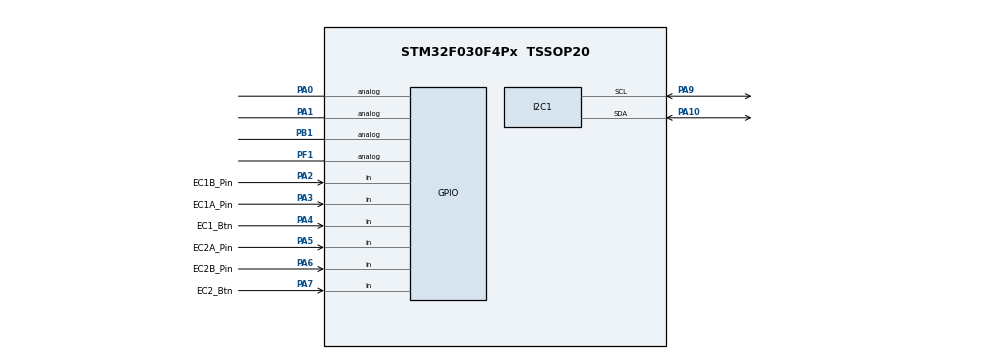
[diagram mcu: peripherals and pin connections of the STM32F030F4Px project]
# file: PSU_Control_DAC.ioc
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Mcu.Family=STM32F0
Mcu.Name=STM32F030F4Px
Mcu.Package=TSSOP20
Mcu.UserConstants=SCAN_PERIOD_US,100
NVIC.TIM14_IRQn=true\:0\:0\:false\:false\:true\:true\:true
PA0.Signal=GPIO_Analog
PA1.Signal=GPIO_Analog
PA10.Mode=I2C
PA10.Signal=I2C1_SDA
PA13.Mode=Serial_Wire
PA13.Signal=SYS_SWDIO
PA14.Mode=Serial_Wire
PA14.Signal=SYS_SWCLK
PA2.GPIO_Label=EC1B_Pin
PA2.Signal=GPIO_Input
PA3.GPIO_Label=EC1A_Pin
PA3.Signal=GPIO_Input
PA4.GPIO_Label=EC1_Btn
PA4.Signal=GPIO_Input
PA5.GPIO_Label=EC2A_Pin
PA5.Signal=GPIO_Input
PA6.GPIO_Label=EC2B_Pin
PA6.Signal=GPIO_Input
PA7.GPIO_Label=EC2_Btn
PA7.Signal=GPIO_Input
PA9.Mode=I2C
PA9.Signal=I2C1_SCL
PB1.Signal=GPIO_Analog
PF0-OSC_IN.Mode=HSE-External-Clock-Source
PF0-OSC_IN.Signal=RCC_OSC_IN
PF1-OSC_OUT.Signal=GPIO_Analog
ProjectManager.HeapSize=0x200
ProjectManager.StackSize=0x400
ProjectManager.TargetToolchain=STM32CubeIDE
RCC.PLLSourceVirtual=RCC_PLLSOURCE_HSE
RCC.SYSCLKSource=RCC_SYSCLKSOURCE_HSE
TIM14.Period=SCAN_PERIOD_US-1
TIM14.Prescaler=7
VP_TIM14_VS_ClockSourceINT.Mode=Enable_Timer
board=custom

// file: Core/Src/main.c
/* USER CODE BEGIN Header */
/**
  ******************************************************************************
  * @file           : main.c
  * @brief          : Main program body
  ******************************************************************************
  * @attention
  *
  * <h2><center>&copy; Copyright (c) 2024 STMicroelectronics.
  * All rights reserved.</center></h2>
  *
  * This software component is licensed by ST under BSD 3-Clause license,
  * the "License"; You may not use this file except in compliance with the
  * License. You may obtain a copy of the License at:
  *                        opensource.org/licenses/BSD-3-Clause
  *
  ******************************************************************************
  */
/* USER CODE END Header */
#include "main.h"

/* USER CODE BEGIN Includes */
#include "board_controls.h"
#include "mcp4725.h"
#include "calibration.h"
/* USER CODE END Includes */

/* USER CODE BEGIN PD */
#define CURRENT_DAC_ADDR		0x60
#define VOLTAGE_DAC_ADDR		0x61

#define SAVE_EEPROM_DELAY_MS	2000
#define SAVE_EEPROM_DELAY_CNTR	(SAVE_EEPROM_DELAY_MS/STATE_SCAN_PERIOD_MS)

#define STEP_50MV				1
#define STEP_250MV				5
#define STEP_10MA				1
#define STEP_100MA				10
/* USER CODE END PD */

I2C_HandleTypeDef hi2c1;

TIM_HandleTypeDef htim14;

/* USER CODE BEGIN PV */
volatile uint8_t is_scan_event = 0;
uint16_t voltageDacVal = 0, currentDacVal = 0;
uint16_t voltageDacValIdx = 0, currentDacValIdx = 0;

uint16_t voltageValStepArray[2] = {STEP_50MV, STEP_250MV}, currentValStepArray[2] = {STEP_10MA, STEP_100MA};
uint8_t voltageValStepIdx = 0, currentValStepIdx = 0;
uint16_t voltageValStep = STEP_50MV, currentValStep = STEP_10MA;
/* USER CODE END PV */

void SystemClock_Config(void);
static void MX_GPIO_Init(void);
static void MX_I2C1_Init(void);
static void MX_TIM14_Init(void);
/* USER CODE BEGIN PFP */
static void checkDacValLimits(uint16_t* val, uint16_t min, uint16_t max);
static void checkIndexValLimits(uint16_t* val, uint16_t min, uint16_t max);
static uint8_t checkSaveDacValueInEEPROM(uint16_t* delay_cntr);
static uint16_t getDacSavedValueIdx(uint16_t* values, uint16_t max_index, uint16_t saved_val);
/* USER CODE END PFP */

int main(void)
{
  /* USER CODE BEGIN 1 */
  EncoderState enc1 = {0, NotPressed, 0}, enc2 = {0, NotPressed, 0};
  uint16_t saveVoltageValDelayCntr = SAVE_EEPROM_DELAY_CNTR+1, saveCurrentValDelayCntr = SAVE_EEPROM_DELAY_CNTR+1; // no need to save already saved DAC value
  /* USER CODE END 1 */

  /* MCU Configuration--------------------------------------------------------*/

  /* Reset of all peripherals, Initializes the Flash interface and the Systick. */
  HAL_Init();

  /* Configure the system clock */
  SystemClock_Config();

  /* Initialize all configured peripherals */
  MX_GPIO_Init();
  MX_I2C1_Init();
  MX_TIM14_Init();
  /* USER CODE BEGIN 2 */
  // check DACs present on I2C bus and read last saved value from EEPROM
  if(MCP4725_check(VOLTAGE_DAC_ADDR))
  {
	  voltageDacVal = MCP4725_readDAC_register_and_EEPROM(VOLTAGE_DAC_ADDR, DAC_EEPROM_VALUE);
  }
  voltageDacValIdx = getDacSavedValueIdx((uint16_t*)voltage_set_50mv_step, VOLTAGE_MAX_INDEX, voltageDacVal);

  HAL_Delay(100);

  if(MCP4725_check(CURRENT_DAC_ADDR))
  {
	  currentDacVal = MCP4725_readDAC_register_and_EEPROM(CURRENT_DAC_ADDR, DAC_EEPROM_VALUE);
  }
  currentDacValIdx = getDacSavedValueIdx((uint16_t*)current_set_10ma_step, CURRENT_MAX_INDEX, currentDacVal);
  // start encoder scanning timer
  HAL_TIM_Base_Start_IT(&htim14);
  /* USER CODE END 2 */

  /* Infinite loop */
  while (1)
  {

    /* USER CODE BEGIN 3 */
	  if(is_scan_event)
	  {
		  is_scan_event = 0; // reset flag

		  // get encoders state
		  if(scanEncoders(&enc1, &enc2))
		  {
			  // check is encoder 1 state changed
			  if(enc1.is_state_changed)
			  {
				  // set DAC value, if encoder counter value is changed
				  if(enc1.counter_offset != 0)
				  {
					  saveVoltageValDelayCntr = 0; // reset counter
					  voltageDacValIdx += (enc1.counter_offset*voltageValStep);
					  checkIndexValLimits(&voltageDacValIdx, 0, VOLTAGE_MAX_INDEX);
					  voltageDacVal = voltage_set_50mv_step[voltageDacValIdx];
//					  checkDacValLimits(&voltageDacVal, VOLTAGE_MIN_VAL, VOLTAGE_MAX_VAL);
					  MCP4725_writeDAC_register(VOLTAGE_DAC_ADDR, voltageDacVal, 0);
				  }
				  else
				  {
					  // save current DAC value in EEPROM, if it wasn't changed by 2 sec
					  if(checkSaveDacValueInEEPROM(&saveVoltageValDelayCntr))
					  {
						  MCP4725_writeDAC_register(VOLTAGE_DAC_ADDR, voltageDacVal, 1);
					  }
				  }

				  // set DAC value change step, if encoder button is pressed
				  if(enc1.btn_state == Pressed)
				  {
					  voltageValStepIdx ^= 0x01;
					  voltageValStep = voltageValStepArray[voltageValStepIdx];
				  }
				  else if(enc1.btn_state == LongPressed)
				  {
					  voltageValStep = 1; // set maximum accuracy
				  }
			  }
			  else
			  {
				  // save current DAC value in EEPROM, if it wasn't changed by 2 sec
				  if(checkSaveDacValueInEEPROM(&saveVoltageValDelayCntr))
				  {
					  MCP4725_writeDAC_register(VOLTAGE_DAC_ADDR, voltageDacVal, 1);
				  }
			  }

			  // check is encoder 2 state changed
			  if(enc2.is_state_changed)
			  {
				  // set DAC value, if encoder counter value is changed
				  if(enc2.counter_offset != 0)
				  {
					  saveCurrentValDelayCntr = 0; // reset counter
					  currentDacValIdx += (enc2.counter_offset*currentValStep);
					  checkIndexValLimits(&currentDacValIdx, 0, CURRENT_MAX_INDEX);
					  currentDacVal = current_set_10ma_step[currentDacValIdx];
//					  checkDacValLimits(&currentDacVal, CURRENT_MIN_VAL, CURRENT_MAX_VAL);
					  MCP4725_writeDAC_register(CURRENT_DAC_ADDR, currentDacVal, 0);
				  }
				  else
				  {
					  // save current DAC value in EEPROM, if it wasn't changed by 2 sec
					  if(checkSaveDacValueInEEPROM(&saveCurrentValDelayCntr))
					  {
						  MCP4725_writeDAC_register(CURRENT_DAC_ADDR, currentDacVal, 1);
					  }
				  }

				  // set DAC value change step, if encoder button is pressed
				  if(enc2.btn_state == Pressed)
				  {
					  currentValStepIdx ^= 0x01;
					  currentValStep = currentValStepArray[currentValStepIdx];
				  }
				  else if(enc2.btn_state == LongPressed)
				  {
					  currentValStep = 1; // set maximum accuracy
				  }
			  }
			  else
			  {
				  // save current DAC value in EEPROM, if it wasn't changed by 2 sec
				  if(checkSaveDacValueInEEPROM(&saveCurrentValDelayCntr))
				  {
					  MCP4725_writeDAC_register(CURRENT_DAC_ADDR, currentDacVal, 1);
				  }
			  }
		  }
	  }
  }
  /* USER CODE END 3 */
}

void SystemClock_Config(void)
{
  RCC_OscInitTypeDef RCC_OscInitStruct = {0};
  RCC_ClkInitTypeDef RCC_ClkInitStruct = {0};
  RCC_PeriphCLKInitTypeDef PeriphClkInit = {0};

  /** Initializes the RCC Oscillators according to the specified parameters
  * in the RCC_OscInitTypeDef structure.
  */
  RCC_OscInitStruct.OscillatorType = RCC_OSCILLATORTYPE_HSI|RCC_OSCILLATORTYPE_HSE;
  RCC_OscInitStruct.HSEState = RCC_HSE_BYPASS;
  RCC_OscInitStruct.HSIState = RCC_HSI_ON;
  RCC_OscInitStruct.HSICalibrationValue = RCC_HSICALIBRATION_DEFAULT;
  RCC_OscInitStruct.PLL.PLLState = RCC_PLL_NONE;
  if (HAL_RCC_OscConfig(&RCC_OscInitStruct) != HAL_OK)
  {
    Error_Handler();
  }
  /** Initializes the CPU, AHB and APB buses clocks
  */
  RCC_ClkInitStruct.ClockType = RCC_CLOCKTYPE_HCLK|RCC_CLOCKTYPE_SYSCLK
                              |RCC_CLOCKTYPE_PCLK1;
  RCC_ClkInitStruct.SYSCLKSource = RCC_SYSCLKSOURCE_HSE;
  RCC_ClkInitStruct.AHBCLKDivider = RCC_SYSCLK_DIV1;
  RCC_ClkInitStruct.APB1CLKDivider = RCC_HCLK_DIV1;

  if (HAL_RCC_ClockConfig(&RCC_ClkInitStruct, FLASH_LATENCY_0) != HAL_OK)
  {
    Error_Handler();
  }
  PeriphClkInit.PeriphClockSelection = RCC_PERIPHCLK_I2C1;
  PeriphClkInit.I2c1ClockSelection = RCC_I2C1CLKSOURCE_HSI;
  if (HAL_RCCEx_PeriphCLKConfig(&PeriphClkInit) != HAL_OK)
  {
    Error_Handler();
  }
}

static void MX_I2C1_Init(void)
{

  hi2c1.Instance = I2C1;
  hi2c1.Init.Timing = 0x2000090E;
  hi2c1.Init.OwnAddress1 = 0;
  hi2c1.Init.AddressingMode = I2C_ADDRESSINGMODE_7BIT;
  hi2c1.Init.DualAddressMode = I2C_DUALADDRESS_DISABLE;
  hi2c1.Init.OwnAddress2 = 0;
  hi2c1.Init.OwnAddress2Masks = I2C_OA2_NOMASK;
  hi2c1.Init.GeneralCallMode = I2C_GENERALCALL_DISABLE;
  hi2c1.Init.NoStretchMode = I2C_NOSTRETCH_DISABLE;
  if (HAL_I2C_Init(&hi2c1) != HAL_OK)
  {
    Error_Handler();
  }
  /** Configure Analogue filter
  */
  if (HAL_I2CEx_ConfigAnalogFilter(&hi2c1, I2C_ANALOGFILTER_ENABLE) != HAL_OK)
  {
    Error_Handler();
  }
  /** Configure Digital filter
  */
  if (HAL_I2CEx_ConfigDigitalFilter(&hi2c1, 0) != HAL_OK)
  {
    Error_Handler();
  }

}

static void MX_TIM14_Init(void)
{

  htim14.Instance = TIM14;
  htim14.Init.Prescaler = 7;
  htim14.Init.CounterMode = TIM_COUNTERMODE_UP;
  htim14.Init.Period = SCAN_PERIOD_US-1;
  htim14.Init.ClockDivision = TIM_CLOCKDIVISION_DIV1;
  htim14.Init.AutoReloadPreload = TIM_AUTORELOAD_PRELOAD_DISABLE;
  if (HAL_TIM_Base_Init(&htim14) != HAL_OK)
  {
    Error_Handler();
  }

}

static void MX_GPIO_Init(void)
{
  GPIO_InitTypeDef GPIO_InitStruct = {0};

  /* GPIO Ports Clock Enable */
  __HAL_RCC_GPIOF_CLK_ENABLE();
  __HAL_RCC_GPIOA_CLK_ENABLE();
  __HAL_RCC_GPIOB_CLK_ENABLE();

  /*Configure GPIO pin : PF1 */
  GPIO_InitStruct.Pin = GPIO_PIN_1;
  GPIO_InitStruct.Mode = GPIO_MODE_ANALOG;
  GPIO_InitStruct.Pull = GPIO_NOPULL;
  HAL_GPIO_Init(GPIOF, &GPIO_InitStruct);

  /*Configure GPIO pins : PA0 PA1 */
  GPIO_InitStruct.Pin = GPIO_PIN_0|GPIO_PIN_1;
  GPIO_InitStruct.Mode = GPIO_MODE_ANALOG;
  GPIO_InitStruct.Pull = GPIO_NOPULL;
  HAL_GPIO_Init(GPIOA, &GPIO_InitStruct);

  /*Configure GPIO pins : EC1B_Pin_Pin EC1A_Pin_Pin EC1_Btn_Pin EC2A_Pin_Pin
                           EC2B_Pin_Pin EC2_Btn_Pin */
  GPIO_InitStruct.Pin = EC1B_Pin|EC1A_Pin|EC1_Btn|EC2A_Pin
                          |EC2B_Pin|EC2_Btn;
  GPIO_InitStruct.Mode = GPIO_MODE_INPUT;
  GPIO_InitStruct.Pull = GPIO_NOPULL;
  HAL_GPIO_Init(GPIOA, &GPIO_InitStruct);

  /*Configure GPIO pin : PB1 */
  GPIO_InitStruct.Pin = GPIO_PIN_1;
  GPIO_InitStruct.Mode = GPIO_MODE_ANALOG;
  GPIO_InitStruct.Pull = GPIO_NOPULL;
  HAL_GPIO_Init(GPIOB, &GPIO_InitStruct);

}

/* USER CODE BEGIN 4 */
/**
  * @brief  Period elapsed callback in non-blocking mode
  * @param  htim TIM handle
  * @retval None
  */
void HAL_TIM_PeriodElapsedCallback(TIM_HandleTypeDef *htim)
{
  if(htim->Instance == TIM14)
  {
	  is_scan_event = 1;
  }
}

/**
  * @brief  Check is set DAC value in limits. if not, set limit value
  * @param  val - DAC value pointer
  * @param	min - minimum value limit
  * @param	max - maximum value limit
  * @retval None
  */
static void checkDacValLimits(uint16_t* val, uint16_t min, uint16_t max)
{
	if(*val < min || *val > 32767) // account, that val is unsigned
	{
		*val = min;
	}
	else if(*val > max)
	{
		*val = max;
	}
}

static void checkIndexValLimits(uint16_t* val, uint16_t min, uint16_t max)
{
	if(*val < min || *val > 32767) // account, that val is unsigned
	{
		*val = min;
	}
	else if(*val > max)
	{
		*val = max;
	}
}

/**
  * @brief  Check save DAC value delay after last encoder changed state
  * @param  delay_cntr - delay counter pointer
  * @retval None
  */
static uint8_t checkSaveDacValueInEEPROM(uint16_t* delay_cntr)
{
	uint8_t res = 0;

	if((*delay_cntr) < SAVE_EEPROM_DELAY_CNTR)
	{
	  (*delay_cntr)++;
	}
	else if((*delay_cntr) == SAVE_EEPROM_DELAY_CNTR)
	{
	  res = 1;
	  (*delay_cntr)++; // prevent to multiple saving DAC value
	}

	return res;
}

/**
  * @brief  Get DAC saved value index
  * @param  values - DAC values array
  * @param  saved_val - DAC saved value
  * @retval None
  */
static uint16_t getDacSavedValueIdx(uint16_t* values, uint16_t max_index, uint16_t saved_val)
{
	for(uint16_t i = 0; i < max_index; i++)
	{
		if(values[i] == saved_val)
		{
			return i;
		}
		else if(i > 0 && i < max_index)
		{
			if(values[i-1] < saved_val && values[i+1] > saved_val)
			{
				return i;
			}
		}
	}
	return 0;
}
/* USER CODE END 4 */

void Error_Handler(void)
{
  __disable_irq();
  while (1)
  {
  }
}
